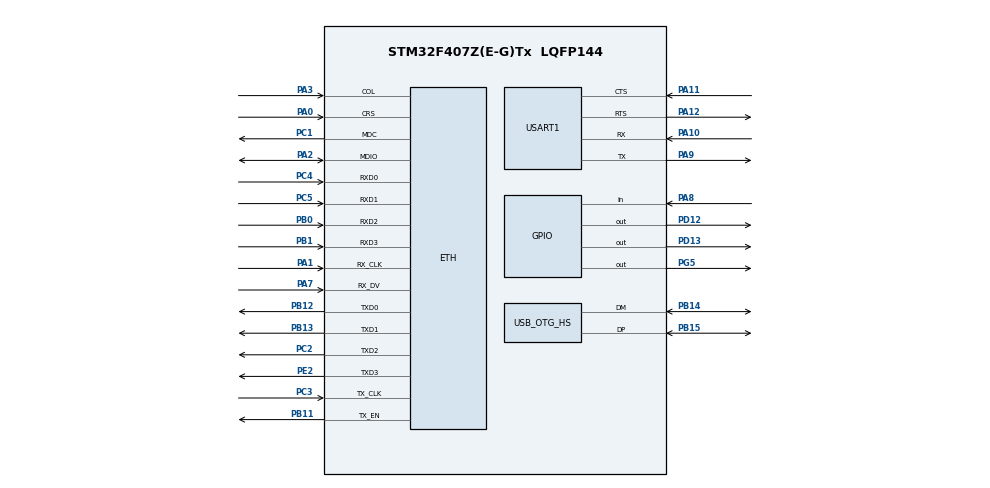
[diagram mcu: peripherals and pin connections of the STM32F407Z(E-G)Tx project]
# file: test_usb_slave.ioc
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LWIP.Version=v1.5.0_RC0_20160211
Mcu.Family=STM32F4
Mcu.Name=STM32F407Z(E-G)Tx
Mcu.Package=LQFP144
NVIC.OTG_HS_IRQn=true\:0\:0\:false\:false\:true
NVIC.PriorityGroup=NVIC_PRIORITYGROUP_4
PA0-WKUP.Mode=MII
PA0-WKUP.Signal=ETH_CRS
PA1.Mode=MII
PA1.Signal=ETH_RX_CLK
PA10.Mode=Asynchronous
PA10.Signal=USART1_RX
PA11.Mode=CTS_RTS
PA11.Signal=USART1_CTS
PA12.Mode=CTS_RTS
PA12.Signal=USART1_RTS
PA2.Mode=MII
PA2.Signal=ETH_MDIO
PA3.Mode=MII
PA3.Signal=ETH_COL
PA7.Mode=MII
PA7.Signal=ETH_RX_DV
PA8.Signal=GPIO_Input
PA9.Mode=Asynchronous
PA9.Signal=USART1_TX
PB0.Mode=MII
PB0.Signal=ETH_RXD2
PB1.Mode=MII
PB1.Signal=ETH_RXD3
PB11.Mode=MII
PB11.Signal=ETH_TX_EN
PB12.Mode=MII
PB12.Signal=ETH_TXD0
PB13.Mode=MII
PB13.Signal=ETH_TXD1
PB14.Mode=Host_FS
PB14.Signal=USB_OTG_HS_DM
PB15.Mode=Host_FS
PB15.Signal=USB_OTG_HS_DP
PC1.Mode=MII
PC1.Signal=ETH_MDC
PC2.Mode=MII
PC2.Signal=ETH_TXD2
PC3.Mode=MII
PC3.Signal=ETH_TX_CLK
PC4.Mode=MII
PC4.Signal=ETH_RXD0
PC5.Mode=MII
PC5.Signal=ETH_RXD1
PD12.Signal=GPIO_Output
PD13.Signal=GPIO_Output
PE2.Mode=MII
PE2.Signal=ETH_TXD3
PG5.Signal=GPIO_Output
ProjectManager.HeapSize=0x200
ProjectManager.StackSize=0x400
ProjectManager.TargetToolchain=MDK-ARM V5
RCC.48MHZClocksFreq_Value=48000000
RCC.AHBFreq_Value=16000000
RCC.APB1Freq_Value=16000000
RCC.APB1TimFreq_Value=16000000
RCC.APB2Freq_Value=16000000
RCC.APB2TimFreq_Value=16000000
RCC.CortexFreq_Value=16000000
RCC.HCLKFreq_Value=16000000
RCC.HSE_VALUE=25000000
RCC.HSI_VALUE=16000000
RCC.LSE_VALUE=32768
RCC.PLLSourceVirtualString=RCC_PLLSOURCE_HSI
RCC.SYSCLKFreq_VALUE=16000000
RCC.VCOOutputFreq_Value=192000000
USB_HOST.USBH_HandleTypeDef-CDC_HS=hUsbHostHS
USB_HOST.VirtualModeHS=Cdc
USB_OTG_HS.VirtualMode-Host_FS=Host_FS
VP_LWIP_VS_Enabled.Mode=Enabled
VP_USB_HOST_VS_USB_HOST_CDC_HS.Mode=CDC_HS
board=test_usb_slave

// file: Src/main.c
/**
  ******************************************************************************
  * File Name          : main.c
  * Description        : Main program body
  ******************************************************************************
  *
  * COPYRIGHT(c) 2016 STMicroelectronics
  *
  * Redistribution and use in source and binary forms, with or without modification,
  * are permitted provided that the following conditions are met:
  *   1. Redistributions of source code must retain the above copyright notice,
  *      this list of conditions and the following disclaimer.
  *   2. Redistributions in binary form must reproduce the above copyright notice,
  *      this list of conditions and the following disclaimer in the documentation
  *      and/or other materials provided with the distribution.
  *   3. Neither the name of STMicroelectronics nor the names of its contributors
  *      may be used to endorse or promote products derived from this software
  *      without specific prior written permission.
  *
  * THIS SOFTWARE IS PROVIDED BY THE COPYRIGHT HOLDERS AND CONTRIBUTORS "AS IS"
  * AND ANY EXPRESS OR IMPLIED WARRANTIES, INCLUDING, BUT NOT LIMITED TO, THE
  * IMPLIED WARRANTIES OF MERCHANTABILITY AND FITNESS FOR A PARTICULAR PURPOSE ARE
  * DISCLAIMED. IN NO EVENT SHALL THE COPYRIGHT HOLDER OR CONTRIBUTORS BE LIABLE
  * FOR ANY DIRECT, INDIRECT, INCIDENTAL, SPECIAL, EXEMPLARY, OR CONSEQUENTIAL
  * DAMAGES (INCLUDING, BUT NOT LIMITED TO, PROCUREMENT OF SUBSTITUTE GOODS OR
  * SERVICES; LOSS OF USE, DATA, OR PROFITS; OR BUSINESS INTERRUPTION) HOWEVER
  * CAUSED AND ON ANY THEORY OF LIABILITY, WHETHER IN CONTRACT, STRICT LIABILITY,
  * OR TORT (INCLUDING NEGLIGENCE OR OTHERWISE) ARISING IN ANY WAY OUT OF THE USE
  * OF THIS SOFTWARE, EVEN IF ADVISED OF THE POSSIBILITY OF SUCH DAMAGE.
  *
  ******************************************************************************
  */
#include "stm32f4xx_hal.h"
#include "lwip.h"
#include "usb_host.h"
#include "board.h"

UART_HandleTypeDef huart1;

/* USER CODE BEGIN PV */
/* Private variables ---------------------------------------------------------*/

/* USER CODE END PV */

void SystemClock_Config(void);
void Error_Handler(void);
static void MX_GPIO_Init(void);
static void MX_USART1_UART_Init(void);
static void LTE_Enable(void);
void MX_USB_HOST_Process(void);

/* USER CODE BEGIN PFP */
/* Private function prototypes -----------------------------------------------*/

/* USER CODE END PFP */

int main(void)
{

  /* MCU Configuration----------------------------------------------------------*/

  /* Reset of all peripherals, Initializes the Flash interface and the Systick. */
  HAL_Init();

  /* Configure the system clock */
  SystemClock_Config();

  /* Initialize all configured peripherals */
  MX_GPIO_Init();
  MX_USART1_UART_Init();
  MX_LWIP_Init();
  MX_USB_HOST_Init();
	LTE_Enable();

  /* Infinite loop */
  while (1)
  {
    MX_USB_HOST_Process();

  }

}

/** System Clock Configuration
*/
void SystemClock_Config(void)
{

  RCC_OscInitTypeDef RCC_OscInitStruct;
  RCC_ClkInitTypeDef RCC_ClkInitStruct;
  RCC_PeriphCLKInitTypeDef PeriphClkInitStruct;
  __HAL_RCC_PWR_CLK_ENABLE();

  __HAL_PWR_VOLTAGESCALING_CONFIG(PWR_REGULATOR_VOLTAGE_SCALE1);

  RCC_OscInitStruct.OscillatorType = RCC_OSCILLATORTYPE_LSI|RCC_OSCILLATORTYPE_HSE;
  RCC_OscInitStruct.HSEState = RCC_HSE_ON;
  RCC_OscInitStruct.LSIState = RCC_LSI_ON;
  RCC_OscInitStruct.PLL.PLLState = RCC_PLL_ON;
  RCC_OscInitStruct.PLL.PLLSource = RCC_PLLSOURCE_HSE;
  RCC_OscInitStruct.PLL.PLLM = 25;
  RCC_OscInitStruct.PLL.PLLN = 336;
  RCC_OscInitStruct.PLL.PLLP = RCC_PLLP_DIV2;
  RCC_OscInitStruct.PLL.PLLQ = 7;
  if (HAL_RCC_OscConfig(&RCC_OscInitStruct) != HAL_OK)
  {
    Error_Handler();
  }

  RCC_ClkInitStruct.ClockType = RCC_CLOCKTYPE_SYSCLK|RCC_CLOCKTYPE_PCLK1
                              |RCC_CLOCKTYPE_PCLK2;
  RCC_ClkInitStruct.SYSCLKSource = RCC_SYSCLKSOURCE_PLLCLK;
  RCC_ClkInitStruct.AHBCLKDivider = RCC_SYSCLK_DIV1;
  RCC_ClkInitStruct.APB1CLKDivider = RCC_HCLK_DIV16;
  RCC_ClkInitStruct.APB2CLKDivider = RCC_HCLK_DIV2;
  if (HAL_RCC_ClockConfig(&RCC_ClkInitStruct, FLASH_LATENCY_5) != HAL_OK)
  {
    Error_Handler();
  }
  PeriphClkInitStruct.PeriphClockSelection = RCC_PERIPHCLK_RTC;
  PeriphClkInitStruct.RTCClockSelection = RCC_RTCCLKSOURCE_LSI;
  HAL_RCCEx_PeriphCLKConfig(&PeriphClkInitStruct);
}

/* USART1 init function */
static void MX_USART1_UART_Init(void)
{

  huart1.Instance = USART1;
  huart1.Init.BaudRate = 115200;
  huart1.Init.WordLength = UART_WORDLENGTH_8B;
  huart1.Init.StopBits = UART_STOPBITS_1;
  huart1.Init.Parity = UART_PARITY_NONE;
  huart1.Init.Mode = UART_MODE_TX_RX;
  huart1.Init.HwFlowCtl = UART_HWCONTROL_RTS_CTS;
  huart1.Init.OverSampling = UART_OVERSAMPLING_16;
  if (HAL_UART_Init(&huart1) != HAL_OK)
  {
    Error_Handler();
  }

}

/** Configure pins as
        * Analog
        * Input
        * Output
        * EVENT_OUT
        * EXTI
*/
static void MX_GPIO_Init(void)
{

  GPIO_InitTypeDef GPIO_InitStruct;

  /* GPIO Ports Clock Enable */
  __HAL_RCC_GPIOE_CLK_ENABLE();
  __HAL_RCC_GPIOC_CLK_ENABLE();
  __HAL_RCC_GPIOA_CLK_ENABLE();
  __HAL_RCC_GPIOB_CLK_ENABLE();
  __HAL_RCC_GPIOD_CLK_ENABLE();
  __HAL_RCC_GPIOG_CLK_ENABLE();

  /*Configure GPIO pin Output Level */
  HAL_GPIO_WritePin(GPIOD, GPIO_PIN_12|GPIO_PIN_13, GPIO_PIN_RESET);

  /*Configure GPIO pin Output Level */
  HAL_GPIO_WritePin(GPIOG, GPIO_PIN_5, GPIO_PIN_RESET);

  /*Configure GPIO pins : PD12 PD13 */
  GPIO_InitStruct.Pin = GPIO_PIN_12|GPIO_PIN_13;
  GPIO_InitStruct.Mode = GPIO_MODE_OUTPUT_PP;
  GPIO_InitStruct.Pull = GPIO_NOPULL;
  GPIO_InitStruct.Speed = GPIO_SPEED_FREQ_LOW;
  HAL_GPIO_Init(GPIOD, &GPIO_InitStruct);

  /*Configure GPIO pin : PG5 */
  GPIO_InitStruct.Pin = GPIO_PIN_5;
  GPIO_InitStruct.Mode = GPIO_MODE_OUTPUT_PP;
  GPIO_InitStruct.Pull = GPIO_NOPULL;
  GPIO_InitStruct.Speed = GPIO_SPEED_FREQ_LOW;
  HAL_GPIO_Init(GPIOG, &GPIO_InitStruct);

  /*Configure GPIO pin : PA8 */
  GPIO_InitStruct.Pin = GPIO_PIN_8;
  GPIO_InitStruct.Mode = GPIO_MODE_INPUT;
  GPIO_InitStruct.Pull = GPIO_NOPULL;
  HAL_GPIO_Init(GPIOA, &GPIO_InitStruct);

}

void Error_Handler(void)
{
  /* USER CODE BEGIN Error_Handler */
  /* User can add his own implementation to report the HAL error return state */
  while(1)
  {
			HAL_Delay(500);
			BSP_LED_Toggle(LED3);
  }
  /* USER CODE END Error_Handler */
}
static void LTE_Enable(void)
{
	 HAL_GPIO_WritePin(GPIOG, GPIO_PIN_5, GPIO_PIN_SET);
}

/************************ (C) COPYRIGHT STMicroelectronics *****END OF FILE****/
